VERSION 5.7 ;
  NOWIREEXTENSIONATPIN ON ;
  DIVIDERCHAR "/" ;
  BUSBITCHARS "[]" ;
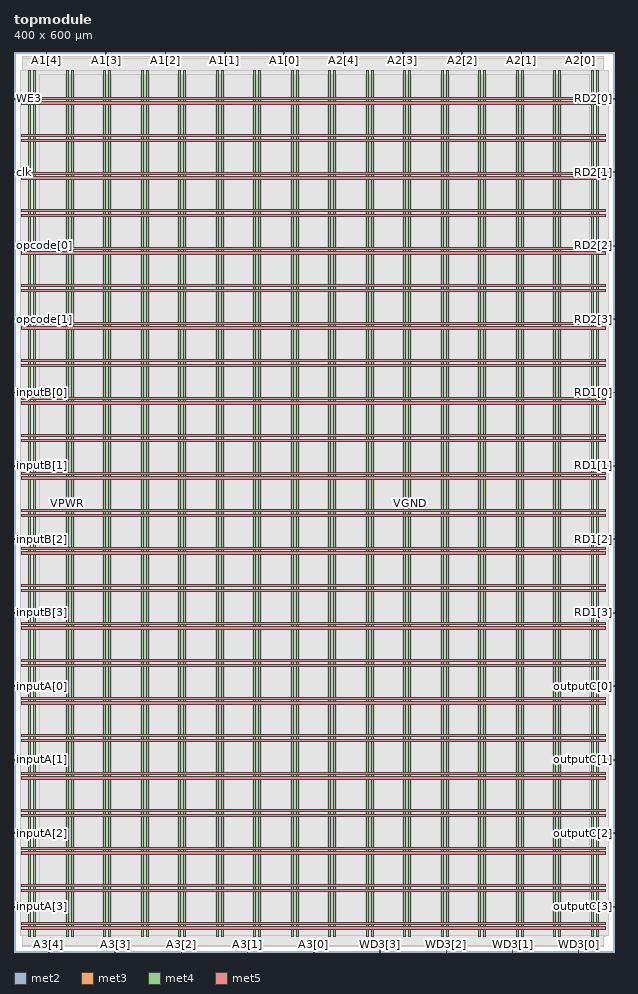
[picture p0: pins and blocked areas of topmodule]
MACRO topmodule
  CLASS BLOCK ;
  FOREIGN topmodule ;
  ORIGIN 0.000 0.000 ;
  SIZE 400.000 BY 600.000 ;
  PIN A1[0]
    DIRECTION INPUT ;
    USE SIGNAL ;
    ANTENNAGATEAREA 0.990000 ;
    ANTENNADIFFAREA 0.434700 ;
    PORT
      LAYER met2 ;
        RECT 179.950 596.000 180.230 600.000 ;
    END
  END A1[0]
  PIN A1[1]
    DIRECTION INPUT ;
    USE SIGNAL ;
    ANTENNAGATEAREA 0.426000 ;
    ANTENNADIFFAREA 0.434700 ;
    PORT
      LAYER met2 ;
        RECT 140.390 596.000 140.670 600.000 ;
    END
  END A1[1]
  PIN A1[2]
    DIRECTION INPUT ;
    USE SIGNAL ;
    ANTENNAGATEAREA 0.852000 ;
    ANTENNADIFFAREA 0.434700 ;
    PORT
      LAYER met2 ;
        RECT 100.830 596.000 101.110 600.000 ;
    END
  END A1[2]
  PIN A1[3]
    DIRECTION INPUT ;
    USE SIGNAL ;
    ANTENNAGATEAREA 0.990000 ;
    ANTENNADIFFAREA 0.434700 ;
    PORT
      LAYER met2 ;
        RECT 61.270 596.000 61.550 600.000 ;
    END
  END A1[3]
  PIN A1[4]
    DIRECTION INPUT ;
    USE SIGNAL ;
    ANTENNAGATEAREA 0.742500 ;
    ANTENNADIFFAREA 0.434700 ;
    PORT
      LAYER met2 ;
        RECT 21.710 596.000 21.990 600.000 ;
    END
  END A1[4]
  PIN A2[0]
    DIRECTION INPUT ;
    USE SIGNAL ;
    ANTENNAGATEAREA 0.990000 ;
    ANTENNADIFFAREA 0.434700 ;
    PORT
      LAYER met2 ;
        RECT 377.750 596.000 378.030 600.000 ;
    END
  END A2[0]
  PIN A2[1]
    DIRECTION INPUT ;
    USE SIGNAL ;
    ANTENNAGATEAREA 2.446500 ;
    ANTENNADIFFAREA 1.304100 ;
    PORT
      LAYER met2 ;
        RECT 338.190 596.000 338.470 600.000 ;
    END
  END A2[1]
  PIN A2[2]
    DIRECTION INPUT ;
    USE SIGNAL ;
    ANTENNAGATEAREA 0.990000 ;
    ANTENNADIFFAREA 0.434700 ;
    PORT
      LAYER met2 ;
        RECT 298.630 596.000 298.910 600.000 ;
    END
  END A2[2]
  PIN A2[3]
    DIRECTION INPUT ;
    USE SIGNAL ;
    ANTENNAGATEAREA 0.495000 ;
    ANTENNADIFFAREA 0.434700 ;
    PORT
      LAYER met2 ;
        RECT 259.070 596.000 259.350 600.000 ;
    END
  END A2[3]
  PIN A2[4]
    DIRECTION INPUT ;
    USE SIGNAL ;
    ANTENNAGATEAREA 0.742500 ;
    ANTENNADIFFAREA 0.434700 ;
    PORT
      LAYER met2 ;
        RECT 219.510 596.000 219.790 600.000 ;
    END
  END A2[4]
  PIN A3[0]
    DIRECTION INPUT ;
    USE SIGNAL ;
    ANTENNAGATEAREA 0.742500 ;
    ANTENNADIFFAREA 0.434700 ;
    PORT
      LAYER met2 ;
        RECT 199.730 0.000 200.010 4.000 ;
    END
  END A3[0]
  PIN A3[1]
    DIRECTION INPUT ;
    USE SIGNAL ;
    ANTENNAGATEAREA 0.852000 ;
    ANTENNADIFFAREA 0.434700 ;
    PORT
      LAYER met2 ;
        RECT 155.570 0.000 155.850 4.000 ;
    END
  END A3[1]
  PIN A3[2]
    DIRECTION INPUT ;
    USE SIGNAL ;
    ANTENNAGATEAREA 0.852000 ;
    ANTENNADIFFAREA 0.434700 ;
    PORT
      LAYER met2 ;
        RECT 111.410 0.000 111.690 4.000 ;
    END
  END A3[2]
  PIN A3[3]
    DIRECTION INPUT ;
    USE SIGNAL ;
    ANTENNAGATEAREA 0.852000 ;
    ANTENNADIFFAREA 0.434700 ;
    PORT
      LAYER met2 ;
        RECT 67.250 0.000 67.530 4.000 ;
    END
  END A3[3]
  PIN A3[4]
    DIRECTION INPUT ;
    USE SIGNAL ;
    ANTENNAGATEAREA 0.990000 ;
    ANTENNADIFFAREA 0.434700 ;
    PORT
      LAYER met2 ;
        RECT 23.090 0.000 23.370 4.000 ;
    END
  END A3[4]
  PIN RD1[0]
    DIRECTION OUTPUT ;
    USE SIGNAL ;
    ANTENNADIFFAREA 0.340600 ;
    PORT
      LAYER met3 ;
        RECT 396.000 372.680 400.000 373.280 ;
    END
  END RD1[0]
  PIN RD1[1]
    DIRECTION OUTPUT ;
    USE SIGNAL ;
    ANTENNADIFFAREA 0.340600 ;
    PORT
      LAYER met3 ;
        RECT 396.000 323.720 400.000 324.320 ;
    END
  END RD1[1]
  PIN RD1[2]
    DIRECTION OUTPUT ;
    USE SIGNAL ;
    ANTENNADIFFAREA 0.340600 ;
    PORT
      LAYER met3 ;
        RECT 396.000 274.760 400.000 275.360 ;
    END
  END RD1[2]
  PIN RD1[3]
    DIRECTION OUTPUT ;
    USE SIGNAL ;
    ANTENNADIFFAREA 0.340600 ;
    PORT
      LAYER met3 ;
        RECT 396.000 225.800 400.000 226.400 ;
    END
  END RD1[3]
  PIN RD2[0]
    DIRECTION OUTPUT ;
    USE SIGNAL ;
    ANTENNADIFFAREA 0.340600 ;
    PORT
      LAYER met3 ;
        RECT 396.000 568.520 400.000 569.120 ;
    END
  END RD2[0]
  PIN RD2[1]
    DIRECTION OUTPUT ;
    USE SIGNAL ;
    ANTENNADIFFAREA 0.340600 ;
    PORT
      LAYER met3 ;
        RECT 396.000 519.560 400.000 520.160 ;
    END
  END RD2[1]
  PIN RD2[2]
    DIRECTION OUTPUT ;
    USE SIGNAL ;
    ANTENNADIFFAREA 0.340600 ;
    PORT
      LAYER met3 ;
        RECT 396.000 470.600 400.000 471.200 ;
    END
  END RD2[2]
  PIN RD2[3]
    DIRECTION OUTPUT ;
    USE SIGNAL ;
    ANTENNADIFFAREA 0.340600 ;
    PORT
      LAYER met3 ;
        RECT 396.000 421.640 400.000 422.240 ;
    END
  END RD2[3]
  PIN VGND
    DIRECTION INOUT ;
    USE GROUND ;
    PORT
      LAYER met4 ;
        RECT 13.020 10.640 14.620 587.760 ;
    END
    PORT
      LAYER met4 ;
        RECT 38.020 10.640 39.620 587.760 ;
    END
    PORT
      LAYER met4 ;
        RECT 63.020 10.640 64.620 587.760 ;
    END
    PORT
      LAYER met4 ;
        RECT 88.020 10.640 89.620 587.760 ;
    END
    PORT
      LAYER met4 ;
        RECT 113.020 10.640 114.620 587.760 ;
    END
    PORT
      LAYER met4 ;
        RECT 138.020 10.640 139.620 587.760 ;
    END
    PORT
      LAYER met4 ;
        RECT 163.020 10.640 164.620 587.760 ;
    END
    PORT
      LAYER met4 ;
        RECT 188.020 10.640 189.620 587.760 ;
    END
    PORT
      LAYER met4 ;
        RECT 213.020 10.640 214.620 587.760 ;
    END
    PORT
      LAYER met4 ;
        RECT 238.020 10.640 239.620 587.760 ;
    END
    PORT
      LAYER met4 ;
        RECT 263.020 10.640 264.620 587.760 ;
    END
    PORT
      LAYER met4 ;
        RECT 288.020 10.640 289.620 587.760 ;
    END
    PORT
      LAYER met4 ;
        RECT 313.020 10.640 314.620 587.760 ;
    END
    PORT
      LAYER met4 ;
        RECT 338.020 10.640 339.620 587.760 ;
    END
    PORT
      LAYER met4 ;
        RECT 363.020 10.640 364.620 587.760 ;
    END
    PORT
      LAYER met4 ;
        RECT 388.020 10.640 389.620 587.760 ;
    END
    PORT
      LAYER met5 ;
        RECT 5.280 18.380 394.460 19.980 ;
    END
    PORT
      LAYER met5 ;
        RECT 5.280 43.380 394.460 44.980 ;
    END
    PORT
      LAYER met5 ;
        RECT 5.280 68.380 394.460 69.980 ;
    END
    PORT
      LAYER met5 ;
        RECT 5.280 93.380 394.460 94.980 ;
    END
    PORT
      LAYER met5 ;
        RECT 5.280 118.380 394.460 119.980 ;
    END
    PORT
      LAYER met5 ;
        RECT 5.280 143.380 394.460 144.980 ;
    END
    PORT
      LAYER met5 ;
        RECT 5.280 168.380 394.460 169.980 ;
    END
    PORT
      LAYER met5 ;
        RECT 5.280 193.380 394.460 194.980 ;
    END
    PORT
      LAYER met5 ;
        RECT 5.280 218.380 394.460 219.980 ;
    END
    PORT
      LAYER met5 ;
        RECT 5.280 243.380 394.460 244.980 ;
    END
    PORT
      LAYER met5 ;
        RECT 5.280 268.380 394.460 269.980 ;
    END
    PORT
      LAYER met5 ;
        RECT 5.280 293.380 394.460 294.980 ;
    END
    PORT
      LAYER met5 ;
        RECT 5.280 318.380 394.460 319.980 ;
    END
    PORT
      LAYER met5 ;
        RECT 5.280 343.380 394.460 344.980 ;
    END
    PORT
      LAYER met5 ;
        RECT 5.280 368.380 394.460 369.980 ;
    END
    PORT
      LAYER met5 ;
        RECT 5.280 393.380 394.460 394.980 ;
    END
    PORT
      LAYER met5 ;
        RECT 5.280 418.380 394.460 419.980 ;
    END
    PORT
      LAYER met5 ;
        RECT 5.280 443.380 394.460 444.980 ;
    END
    PORT
      LAYER met5 ;
        RECT 5.280 468.380 394.460 469.980 ;
    END
    PORT
      LAYER met5 ;
        RECT 5.280 493.380 394.460 494.980 ;
    END
    PORT
      LAYER met5 ;
        RECT 5.280 518.380 394.460 519.980 ;
    END
    PORT
      LAYER met5 ;
        RECT 5.280 543.380 394.460 544.980 ;
    END
    PORT
      LAYER met5 ;
        RECT 5.280 568.380 394.460 569.980 ;
    END
  END VGND
  PIN VPWR
    DIRECTION INOUT ;
    USE POWER ;
    PORT
      LAYER met4 ;
        RECT 9.720 10.640 11.320 587.760 ;
    END
    PORT
      LAYER met4 ;
        RECT 34.720 10.640 36.320 587.760 ;
    END
    PORT
      LAYER met4 ;
        RECT 59.720 10.640 61.320 587.760 ;
    END
    PORT
      LAYER met4 ;
        RECT 84.720 10.640 86.320 587.760 ;
    END
    PORT
      LAYER met4 ;
        RECT 109.720 10.640 111.320 587.760 ;
    END
    PORT
      LAYER met4 ;
        RECT 134.720 10.640 136.320 587.760 ;
    END
    PORT
      LAYER met4 ;
        RECT 159.720 10.640 161.320 587.760 ;
    END
    PORT
      LAYER met4 ;
        RECT 184.720 10.640 186.320 587.760 ;
    END
    PORT
      LAYER met4 ;
        RECT 209.720 10.640 211.320 587.760 ;
    END
    PORT
      LAYER met4 ;
        RECT 234.720 10.640 236.320 587.760 ;
    END
    PORT
      LAYER met4 ;
        RECT 259.720 10.640 261.320 587.760 ;
    END
    PORT
      LAYER met4 ;
        RECT 284.720 10.640 286.320 587.760 ;
    END
    PORT
      LAYER met4 ;
        RECT 309.720 10.640 311.320 587.760 ;
    END
    PORT
      LAYER met4 ;
        RECT 334.720 10.640 336.320 587.760 ;
    END
    PORT
      LAYER met4 ;
        RECT 359.720 10.640 361.320 587.760 ;
    END
    PORT
      LAYER met4 ;
        RECT 384.720 10.640 386.320 587.760 ;
    END
    PORT
      LAYER met5 ;
        RECT 5.280 15.080 394.460 16.680 ;
    END
    PORT
      LAYER met5 ;
        RECT 5.280 40.080 394.460 41.680 ;
    END
    PORT
      LAYER met5 ;
        RECT 5.280 65.080 394.460 66.680 ;
    END
    PORT
      LAYER met5 ;
        RECT 5.280 90.080 394.460 91.680 ;
    END
    PORT
      LAYER met5 ;
        RECT 5.280 115.080 394.460 116.680 ;
    END
    PORT
      LAYER met5 ;
        RECT 5.280 140.080 394.460 141.680 ;
    END
    PORT
      LAYER met5 ;
        RECT 5.280 165.080 394.460 166.680 ;
    END
    PORT
      LAYER met5 ;
        RECT 5.280 190.080 394.460 191.680 ;
    END
    PORT
      LAYER met5 ;
        RECT 5.280 215.080 394.460 216.680 ;
    END
    PORT
      LAYER met5 ;
        RECT 5.280 240.080 394.460 241.680 ;
    END
    PORT
      LAYER met5 ;
        RECT 5.280 265.080 394.460 266.680 ;
    END
    PORT
      LAYER met5 ;
        RECT 5.280 290.080 394.460 291.680 ;
    END
    PORT
      LAYER met5 ;
        RECT 5.280 315.080 394.460 316.680 ;
    END
    PORT
      LAYER met5 ;
        RECT 5.280 340.080 394.460 341.680 ;
    END
    PORT
      LAYER met5 ;
        RECT 5.280 365.080 394.460 366.680 ;
    END
    PORT
      LAYER met5 ;
        RECT 5.280 390.080 394.460 391.680 ;
    END
    PORT
      LAYER met5 ;
        RECT 5.280 415.080 394.460 416.680 ;
    END
    PORT
      LAYER met5 ;
        RECT 5.280 440.080 394.460 441.680 ;
    END
    PORT
      LAYER met5 ;
        RECT 5.280 465.080 394.460 466.680 ;
    END
    PORT
      LAYER met5 ;
        RECT 5.280 490.080 394.460 491.680 ;
    END
    PORT
      LAYER met5 ;
        RECT 5.280 515.080 394.460 516.680 ;
    END
    PORT
      LAYER met5 ;
        RECT 5.280 540.080 394.460 541.680 ;
    END
    PORT
      LAYER met5 ;
        RECT 5.280 565.080 394.460 566.680 ;
    END
  END VPWR
  PIN WD3[0]
    DIRECTION INPUT ;
    USE SIGNAL ;
    ANTENNAGATEAREA 0.742500 ;
    ANTENNADIFFAREA 0.434700 ;
    PORT
      LAYER met2 ;
        RECT 376.370 0.000 376.650 4.000 ;
    END
  END WD3[0]
  PIN WD3[1]
    DIRECTION INPUT ;
    USE SIGNAL ;
    ANTENNAGATEAREA 0.495000 ;
    ANTENNADIFFAREA 0.434700 ;
    PORT
      LAYER met2 ;
        RECT 332.210 0.000 332.490 4.000 ;
    END
  END WD3[1]
  PIN WD3[2]
    DIRECTION INPUT ;
    USE SIGNAL ;
    ANTENNAGATEAREA 0.742500 ;
    ANTENNADIFFAREA 0.434700 ;
    PORT
      LAYER met2 ;
        RECT 288.050 0.000 288.330 4.000 ;
    END
  END WD3[2]
  PIN WD3[3]
    DIRECTION INPUT ;
    USE SIGNAL ;
    ANTENNAGATEAREA 0.742500 ;
    ANTENNADIFFAREA 0.434700 ;
    PORT
      LAYER met2 ;
        RECT 243.890 0.000 244.170 4.000 ;
    END
  END WD3[3]
  PIN WE3
    DIRECTION INPUT ;
    USE SIGNAL ;
    ANTENNAGATEAREA 0.852000 ;
    ANTENNADIFFAREA 0.434700 ;
    PORT
      LAYER met3 ;
        RECT 0.000 568.520 4.000 569.120 ;
    END
  END WE3
  PIN clk
    DIRECTION INPUT ;
    USE SIGNAL ;
    ANTENNAGATEAREA 0.852000 ;
    ANTENNADIFFAREA 0.434700 ;
    PORT
      LAYER met3 ;
        RECT 0.000 519.560 4.000 520.160 ;
    END
  END clk
  PIN inputA[0]
    DIRECTION INPUT ;
    USE SIGNAL ;
    ANTENNAGATEAREA 0.247500 ;
    ANTENNADIFFAREA 0.434700 ;
    PORT
      LAYER met3 ;
        RECT 0.000 176.840 4.000 177.440 ;
    END
  END inputA[0]
  PIN inputA[1]
    DIRECTION INPUT ;
    USE SIGNAL ;
    ANTENNAGATEAREA 0.742500 ;
    ANTENNADIFFAREA 0.434700 ;
    PORT
      LAYER met3 ;
        RECT 0.000 127.880 4.000 128.480 ;
    END
  END inputA[1]
  PIN inputA[2]
    DIRECTION INPUT ;
    USE SIGNAL ;
    ANTENNAGATEAREA 0.852000 ;
    ANTENNADIFFAREA 0.434700 ;
    PORT
      LAYER met3 ;
        RECT 0.000 78.920 4.000 79.520 ;
    END
  END inputA[2]
  PIN inputA[3]
    DIRECTION INPUT ;
    USE SIGNAL ;
    ANTENNAGATEAREA 0.742500 ;
    ANTENNADIFFAREA 0.434700 ;
    PORT
      LAYER met3 ;
        RECT 0.000 29.960 4.000 30.560 ;
    END
  END inputA[3]
  PIN inputB[0]
    DIRECTION INPUT ;
    USE SIGNAL ;
    ANTENNAGATEAREA 0.495000 ;
    ANTENNADIFFAREA 0.434700 ;
    PORT
      LAYER met3 ;
        RECT 0.000 372.680 4.000 373.280 ;
    END
  END inputB[0]
  PIN inputB[1]
    DIRECTION INPUT ;
    USE SIGNAL ;
    ANTENNAGATEAREA 0.990000 ;
    ANTENNADIFFAREA 0.434700 ;
    PORT
      LAYER met3 ;
        RECT 0.000 323.720 4.000 324.320 ;
    END
  END inputB[1]
  PIN inputB[2]
    DIRECTION INPUT ;
    USE SIGNAL ;
    ANTENNAGATEAREA 0.426000 ;
    ANTENNADIFFAREA 0.434700 ;
    PORT
      LAYER met3 ;
        RECT 0.000 274.760 4.000 275.360 ;
    END
  END inputB[2]
  PIN inputB[3]
    DIRECTION INPUT ;
    USE SIGNAL ;
    ANTENNAGATEAREA 0.852000 ;
    ANTENNADIFFAREA 0.434700 ;
    PORT
      LAYER met3 ;
        RECT 0.000 225.800 4.000 226.400 ;
    END
  END inputB[3]
  PIN opcode[0]
    DIRECTION INPUT ;
    USE SIGNAL ;
    ANTENNAGATEAREA 0.426000 ;
    ANTENNADIFFAREA 0.434700 ;
    PORT
      LAYER met3 ;
        RECT 0.000 470.600 4.000 471.200 ;
    END
  END opcode[0]
  PIN opcode[1]
    DIRECTION INPUT ;
    USE SIGNAL ;
    ANTENNAGATEAREA 0.990000 ;
    ANTENNADIFFAREA 0.434700 ;
    PORT
      LAYER met3 ;
        RECT 0.000 421.640 4.000 422.240 ;
    END
  END opcode[1]
  PIN outputC[0]
    DIRECTION OUTPUT ;
    USE SIGNAL ;
    ANTENNADIFFAREA 0.340600 ;
    PORT
      LAYER met3 ;
        RECT 396.000 176.840 400.000 177.440 ;
    END
  END outputC[0]
  PIN outputC[1]
    DIRECTION OUTPUT ;
    USE SIGNAL ;
    ANTENNADIFFAREA 0.340600 ;
    PORT
      LAYER met3 ;
        RECT 396.000 127.880 400.000 128.480 ;
    END
  END outputC[1]
  PIN outputC[2]
    DIRECTION OUTPUT ;
    USE SIGNAL ;
    ANTENNADIFFAREA 0.340600 ;
    PORT
      LAYER met3 ;
        RECT 396.000 78.920 400.000 79.520 ;
    END
  END outputC[2]
  PIN outputC[3]
    DIRECTION OUTPUT ;
    USE SIGNAL ;
    ANTENNADIFFAREA 0.340600 ;
    PORT
      LAYER met3 ;
        RECT 396.000 29.960 400.000 30.560 ;
    END
  END outputC[3]
  OBS
      LAYER nwell ;
        RECT 5.330 10.795 394.410 587.605 ;
      LAYER li1 ;
        RECT 5.520 10.795 394.220 587.605 ;
      LAYER met1 ;
        RECT 5.520 10.640 394.220 587.760 ;
      LAYER met2 ;
        RECT 5.610 595.720 21.430 596.770 ;
        RECT 22.270 595.720 60.990 596.770 ;
        RECT 61.830 595.720 100.550 596.770 ;
        RECT 101.390 595.720 140.110 596.770 ;
        RECT 140.950 595.720 179.670 596.770 ;
        RECT 180.510 595.720 219.230 596.770 ;
        RECT 220.070 595.720 258.790 596.770 ;
        RECT 259.630 595.720 298.350 596.770 ;
        RECT 299.190 595.720 337.910 596.770 ;
        RECT 338.750 595.720 377.470 596.770 ;
        RECT 378.310 595.720 392.750 596.770 ;
        RECT 5.610 4.280 392.750 595.720 ;
        RECT 5.610 4.000 22.810 4.280 ;
        RECT 23.650 4.000 66.970 4.280 ;
        RECT 67.810 4.000 111.130 4.280 ;
        RECT 111.970 4.000 155.290 4.280 ;
        RECT 156.130 4.000 199.450 4.280 ;
        RECT 200.290 4.000 243.610 4.280 ;
        RECT 244.450 4.000 287.770 4.280 ;
        RECT 288.610 4.000 331.930 4.280 ;
        RECT 332.770 4.000 376.090 4.280 ;
        RECT 376.930 4.000 392.750 4.280 ;
      LAYER met3 ;
        RECT 4.000 569.520 396.000 587.685 ;
        RECT 4.400 568.120 395.600 569.520 ;
        RECT 4.000 520.560 396.000 568.120 ;
        RECT 4.400 519.160 395.600 520.560 ;
        RECT 4.000 471.600 396.000 519.160 ;
        RECT 4.400 470.200 395.600 471.600 ;
        RECT 4.000 422.640 396.000 470.200 ;
        RECT 4.400 421.240 395.600 422.640 ;
        RECT 4.000 373.680 396.000 421.240 ;
        RECT 4.400 372.280 395.600 373.680 ;
        RECT 4.000 324.720 396.000 372.280 ;
        RECT 4.400 323.320 395.600 324.720 ;
        RECT 4.000 275.760 396.000 323.320 ;
        RECT 4.400 274.360 395.600 275.760 ;
        RECT 4.000 226.800 396.000 274.360 ;
        RECT 4.400 225.400 395.600 226.800 ;
        RECT 4.000 177.840 396.000 225.400 ;
        RECT 4.400 176.440 395.600 177.840 ;
        RECT 4.000 128.880 396.000 176.440 ;
        RECT 4.400 127.480 395.600 128.880 ;
        RECT 4.000 79.920 396.000 127.480 ;
        RECT 4.400 78.520 395.600 79.920 ;
        RECT 4.000 30.960 396.000 78.520 ;
        RECT 4.400 29.560 395.600 30.960 ;
        RECT 4.000 10.715 396.000 29.560 ;
      LAYER met4 ;
        RECT 16.855 18.535 34.320 585.305 ;
        RECT 36.720 18.535 37.620 585.305 ;
        RECT 40.020 18.535 59.320 585.305 ;
        RECT 61.720 18.535 62.620 585.305 ;
        RECT 65.020 18.535 84.320 585.305 ;
        RECT 86.720 18.535 87.620 585.305 ;
        RECT 90.020 18.535 109.320 585.305 ;
        RECT 111.720 18.535 112.620 585.305 ;
        RECT 115.020 18.535 134.320 585.305 ;
        RECT 136.720 18.535 137.620 585.305 ;
        RECT 140.020 18.535 159.320 585.305 ;
        RECT 161.720 18.535 162.620 585.305 ;
        RECT 165.020 18.535 184.320 585.305 ;
        RECT 186.720 18.535 187.620 585.305 ;
        RECT 190.020 18.535 209.320 585.305 ;
        RECT 211.720 18.535 212.620 585.305 ;
        RECT 215.020 18.535 234.320 585.305 ;
        RECT 236.720 18.535 237.620 585.305 ;
        RECT 240.020 18.535 259.320 585.305 ;
        RECT 261.720 18.535 262.620 585.305 ;
        RECT 265.020 18.535 284.320 585.305 ;
        RECT 286.720 18.535 287.620 585.305 ;
        RECT 290.020 18.535 309.320 585.305 ;
        RECT 311.720 18.535 312.620 585.305 ;
        RECT 315.020 18.535 334.320 585.305 ;
        RECT 336.720 18.535 337.620 585.305 ;
        RECT 340.020 18.535 359.320 585.305 ;
        RECT 361.720 18.535 362.620 585.305 ;
        RECT 365.020 18.535 383.345 585.305 ;
  END
END topmodule
END LIBRARY

